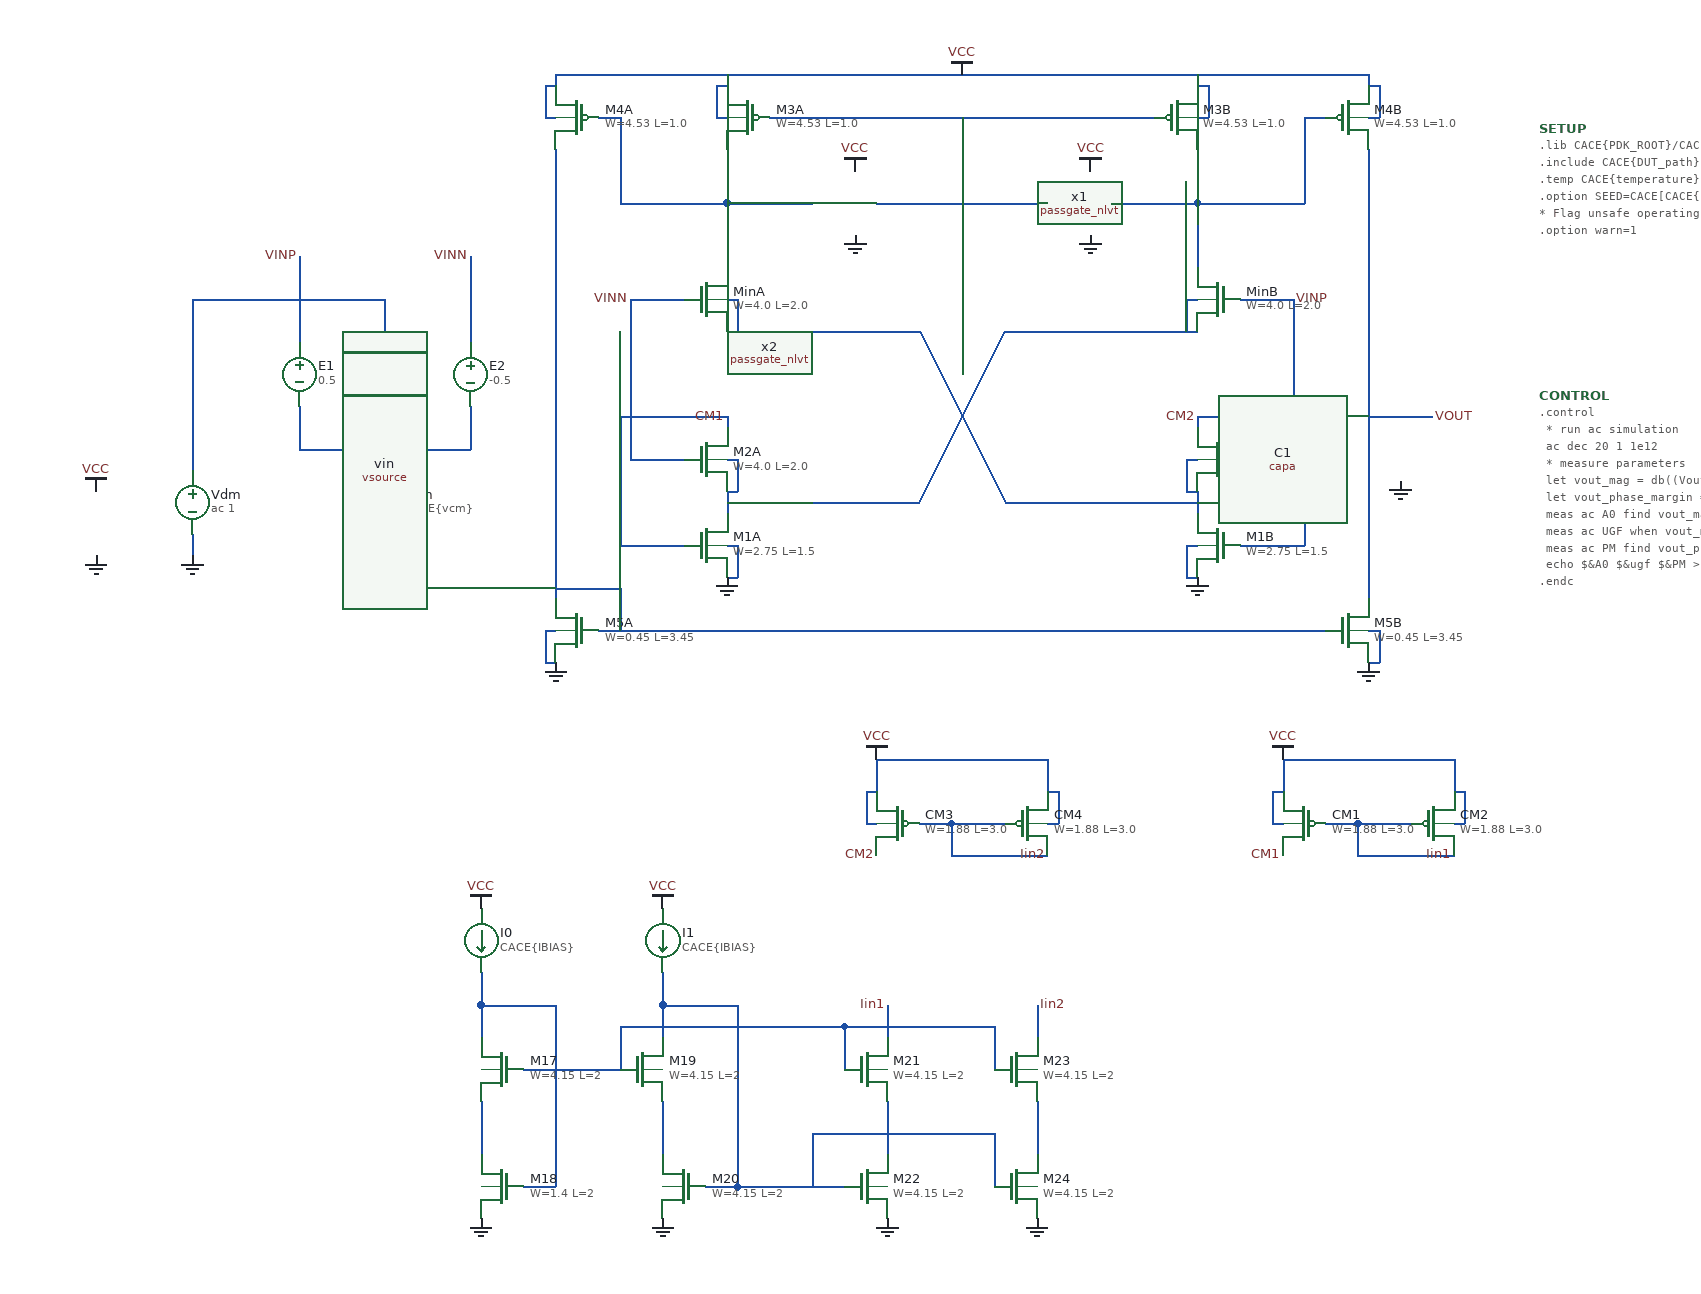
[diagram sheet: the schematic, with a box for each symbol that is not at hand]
v {xschem version=3.4.5 file_version=1.2
}
G {}
K {}
V {}
S {}
E {}
N 220 0 220 10 {
lab=CM2}
N -220 70 -220 90 {
lab=#net1}
N -320 0 -220 0 {
lab=CM1}
N -320 0 -320 120 {
lab=CM1}
N -320 120 -260 120 {
lab=CM1}
N 220 70 220 90 {
lab=#net2}
N -310 40 -260 40 {
lab=VINN}
N -310 -110 -260 -110 {
lab=VINN}
N 260 120 320 120 {
lab=CM2}
N 220 0 320 0 {
lab=CM2}
N 320 0 320 120 {
lab=CM2}
N 260 40 310 40 {
lab=VINP}
N 260 -110 310 -110 {
lab=VINP}
N -220 80 -40 80 {
lab=#net1}
N 40 -80 220 -80 {
lab=#net1}
N -220 -80 -40 -80 {
lab=#net2}
N 40 80 220 80 {
lab=#net2}
N 140 -200 220 -200 {
lab=#net3}
N -220 -200 -140 -200 {
lab=#net4}
N -80 -200 80 -200 {
lab=#net5}
N -180 -280 180 -280 {
lab=#net5}
N -380 -320 380 -320 {
lab=VCC}
N 320 -280 340 -280 {
lab=#net3}
N -340 -280 -320 -280 {
lab=#net4}
N -340 200 340 200 {
lab=#net6}
N -380 -250 -380 170 {
lab=#net6}
N -380 160 -320 160 {
lab=#net6}
N -320 160 -320 200 {
lab=#net6}
N 380 -250 380 170 {
lab=VOUT}
N -380 -320 -380 -310 {
lab=VCC}
N -220 -320 -220 -310 {
lab=VCC}
N 220 -320 220 -310 {
lab=VCC}
N 380 -320 380 -310 {
lab=VCC}
N 380 -0 440 0 {
lab=VOUT}
N -220 -110 -210 -110 {
lab=#net2}
N -210 -110 -210 -80 {
lab=#net2}
N 210 -110 220 -110 {
lab=#net1}
N 210 -110 210 -80 {
lab=#net1}
N -390 200 -380 200 {
lab=GND}
N -390 200 -390 230 {
lab=GND}
N -390 230 -380 230 {
lab=GND}
N -220 120 -210 120 {
lab=GND}
N -210 120 -210 150 {
lab=GND}
N -220 150 -210 150 {
lab=GND}
N -220 40 -210 40 {
lab=#net1}
N -210 40 -210 70 {
lab=#net1}
N -220 70 -210 70 {
lab=#net1}
N 460 380 470 380 {
lab=VCC}
N 470 350 470 380 {
lab=VCC}
N 460 350 470 350 {
lab=VCC}
N 210 120 220 120 {
lab=GND}
N 210 120 210 150 {
lab=GND}
N 210 150 220 150 {
lab=GND}
N 210 40 220 40 {
lab=#net2}
N 210 40 210 70 {
lab=#net2}
N 210 70 220 70 {
lab=#net2}
N 380 200 390 200 {
lab=GND}
N 390 200 390 230 {
lab=GND}
N 380 230 390 230 {
lab=GND}
N 220 -280 230 -280 {
lab=VCC}
N 230 -310 230 -280 {
lab=VCC}
N 220 -310 230 -310 {
lab=VCC}
N 380 -280 390 -280 {
lab=VCC}
N 390 -310 390 -280 {
lab=VCC}
N 380 -310 390 -310 {
lab=VCC}
N -230 -280 -220 -280 {
lab=VCC}
N -230 -310 -230 -280 {
lab=VCC}
N -230 -310 -220 -310 {
lab=VCC}
N -390 -280 -380 -280 {
lab=VCC}
N -390 -310 -390 -280 {
lab=VCC}
N -390 -310 -380 -310 {
lab=VCC}
N -220 0 -220 10 {
lab=CM1}
N 340 380 370 380 {
lab=Iin1}
N 370 380 420 380 {
lab=Iin1}
N 370 380 370 410 {
lab=Iin1}
N 370 410 460 410 {
lab=Iin1}
N 300 320 370 320 {
lab=VCC}
N 370 320 460 320 {
lab=VCC}
N 460 320 460 350 {
lab=VCC}
N 300 320 300 350 {
lab=VCC}
N 290 380 300 380 {
lab=VCC}
N 290 350 300 350 {
lab=VCC}
N 290 350 290 380 {
lab=VCC}
N -320 -280 -320 -200 {
lab=#net4}
N -320 -200 -220 -200 {
lab=#net4}
N 320 -280 320 -200 {
lab=#net3}
N 220 -200 320 -200 {
lab=#net3}
N -40 80 40 -80 {
lab=#net1}
N 220 -250 220 -200 {
lab=#net3}
N 220 -200 220 -140 {
lab=#net3}
N 310 -110 310 40 {
lab=VINP}
N -40 -80 40 80 {
lab=#net2}
N -310 -110 -310 40 {
lab=VINN}
N -220 -250 -220 -200 {
lab=#net4}
N -220 -200 -220 -140 {
lab=#net4}
N 80 380 90 380 {
lab=VCC}
N 90 350 90 380 {
lab=VCC}
N 80 350 90 350 {
lab=VCC}
N -40 380 -10 380 {
lab=Iin2}
N -10 380 40 380 {
lab=Iin2}
N -10 380 -10 410 {
lab=Iin2}
N -10 410 80 410 {
lab=Iin2}
N -80 320 -10 320 {
lab=VCC}
N -10 320 80 320 {
lab=VCC}
N 80 320 80 350 {
lab=VCC}
N -80 320 -80 350 {
lab=VCC}
N -90 380 -80 380 {
lab=VCC}
N -90 350 -80 350 {
lab=VCC}
N -90 350 -90 380 {
lab=VCC}
N -0 -280 -0 -200 {
lab=#net5}
N -540 -60 -500 -60 {
lab=#net7}
N -720 -110 -720 50 {
lab=#net7}
N -720 -110 -540 -110 {
lab=#net7}
N -720 110 -720 130 {
lab=GND}
N -540 110 -540 130 {
lab=GND}
N -540 30 -460 30 {
lab=#net8}
N -540 30 -540 50 {
lab=#net8}
N -540 -20 -500 -20 {
lab=GND}
N -540 -20 -540 0 {
lab=GND}
N -620 -10 -620 30 {
lab=#net8}
N -460 -10 -460 30 {
lab=#net8}
N -540 -110 -540 -60 {
lab=#net7}
N -460 -150 -460 -70 {
lab=VINN}
N -620 -150 -620 -70 {
lab=VINP}
N -620 30 -540 30 {
lab=#net8}
N -580 -20 -540 -20 {
lab=GND}
N -580 -60 -540 -60 {
lab=#net7}
N -450 550 -450 580 {
lab=#net9}
N -450 640 -450 690 {
lab=#net10}
N -410 720 -380 720 {
lab=#net9}
N -380 550 -380 720 {
lab=#net9}
N -450 550 -380 550 {
lab=#net9}
N -280 550 -280 580 {
lab=GND}
N -280 640 -280 690 {
lab=#net11}
N -240 720 -210 720 {
lab=GND}
N -210 550 -210 720 {
lab=GND}
N -280 550 -210 550 {
lab=GND}
N -70 550 -70 580 {
lab=Iin1}
N -70 640 -70 690 {
lab=#net12}
N -410 610 -380 610 {
lab=#net9}
N -210 720 -110 720 {
lab=GND}
N -450 520 -450 550 {
lab=#net9}
N -280 520 -280 550 {
lab=GND}
N -380 610 -320 610 {
lab=#net9}
N -320 570 -320 610 {
lab=#net9}
N -320 570 -110 570 {
lab=#net9}
N -110 570 -110 610 {
lab=#net9}
N 70 550 70 580 {
lab=Iin2}
N 70 640 70 690 {
lab=#net13}
N 30 570 30 610 {
lab=#net9}
N -140 670 -140 720 {
lab=GND}
N -140 670 30 670 {
lab=GND}
N 30 670 30 720 {
lab=GND}
N -110 570 30 570 {
lab=#net9}
C {sky130_fd_pr/nfet_01v8.sym} 240 120 0 1 {name=M1B
W=2.75
L=1.5
nf=1
mult=1
ad="'int((nf+1)/2) * W/nf * 0.29'" 
pd="'2*int((nf+1)/2) * (W/nf + 0.29)'"
as="'int((nf+2)/2) * W/nf * 0.29'" 
ps="'2*int((nf+2)/2) * (W/nf + 0.29)'"
nrd="'0.29 / W'" nrs="'0.29 / W'"
sa=0 sb=0 sd=0
model=nfet_01v8
spiceprefix=X
}
C {sky130_fd_pr/nfet_01v8.sym} 240 40 0 1 {name=M2B
W=4.0
L=2.0
nf=1
mult=1
ad="'int((nf+1)/2) * W/nf * 0.29'" 
pd="'2*int((nf+1)/2) * (W/nf + 0.29)'"
as="'int((nf+2)/2) * W/nf * 0.29'" 
ps="'2*int((nf+2)/2) * (W/nf + 0.29)'"
nrd="'0.29 / W'" nrs="'0.29 / W'"
sa=0 sb=0 sd=0
model=nfet_01v8
spiceprefix=X
}
C {devices/gnd.sym} 220 150 0 0 {name=l1 lab=GND}
C {devices/lab_pin.sym} -310 -110 0 0 {name=p1 sig_type=std_logic lab=VINN}
C {sky130_fd_pr/nfet_01v8.sym} -240 120 0 0 {name=M1A
W=2.75
L=1.5
nf=1
mult=1
ad="'int((nf+1)/2) * W/nf * 0.29'" 
pd="'2*int((nf+1)/2) * (W/nf + 0.29)'"
as="'int((nf+2)/2) * W/nf * 0.29'" 
ps="'2*int((nf+2)/2) * (W/nf + 0.29)'"
nrd="'0.29 / W'" nrs="'0.29 / W'"
sa=0 sb=0 sd=0
model=nfet_01v8
spiceprefix=X
}
C {sky130_fd_pr/nfet_01v8.sym} -240 40 0 0 {name=M2A
W=4.0
L=2.0
nf=1
mult=1
ad="'int((nf+1)/2) * W/nf * 0.29'" 
pd="'2*int((nf+1)/2) * (W/nf + 0.29)'"
as="'int((nf+2)/2) * W/nf * 0.29'" 
ps="'2*int((nf+2)/2) * (W/nf + 0.29)'"
nrd="'0.29 / W'" nrs="'0.29 / W'"
sa=0 sb=0 sd=0
model=nfet_01v8
spiceprefix=X
}
C {devices/gnd.sym} -220 150 0 1 {name=l2 lab=GND}
C {devices/vdd.sym} 300 320 0 0 {name=l3 lab=VCC}
C {sky130_fd_pr/pfet_01v8_lvt.sym} 320 380 0 1 {name=CM1
W=1.88
L=3.0
nf=1
mult=2
ad="'int((nf+1)/2) * W/nf * 0.29'" 
pd="'2*int((nf+1)/2) * (W/nf + 0.29)'"
as="'int((nf+2)/2) * W/nf * 0.29'" 
ps="'2*int((nf+2)/2) * (W/nf + 0.29)'"
nrd="'0.29 / W'" nrs="'0.29 / W'"
sa=0 sb=0 sd=0
model=pfet_01v8_lvt
spiceprefix=X
}
C {sky130_fd_pr/pfet_01v8_lvt.sym} 440 380 0 0 {name=CM2
W=1.88
L=3.0
nf=1
mult=2
ad="'int((nf+1)/2) * W/nf * 0.29'" 
pd="'2*int((nf+1)/2) * (W/nf + 0.29)'"
as="'int((nf+2)/2) * W/nf * 0.29'" 
ps="'2*int((nf+2)/2) * (W/nf + 0.29)'"
nrd="'0.29 / W'" nrs="'0.29 / W'"
sa=0 sb=0 sd=0
model=pfet_01v8_lvt
spiceprefix=X
}
C {devices/lab_pin.sym} 310 -110 0 1 {name=p6 sig_type=std_logic lab=VINP
}
C {sky130_fd_pr/pfet_01v8_lvt.sym} 200 -280 0 0 {name=M3B
W=4.53
L=1.0
nf=1
mult=2
ad="'int((nf+1)/2) * W/nf * 0.29'" 
pd="'2*int((nf+1)/2) * (W/nf + 0.29)'"
as="'int((nf+2)/2) * W/nf * 0.29'" 
ps="'2*int((nf+2)/2) * (W/nf + 0.29)'"
nrd="'0.29 / W'" nrs="'0.29 / W'"
sa=0 sb=0 sd=0
model=pfet_01v8_lvt
spiceprefix=X
}
C {sky130_fd_pr/pfet_01v8_lvt.sym} -200 -280 0 1 {name=M3A
W=4.53
L=1.0
nf=1
mult=2
ad="'int((nf+1)/2) * W/nf * 0.29'" 
pd="'2*int((nf+1)/2) * (W/nf + 0.29)'"
as="'int((nf+2)/2) * W/nf * 0.29'" 
ps="'2*int((nf+2)/2) * (W/nf + 0.29)'"
nrd="'0.29 / W'" nrs="'0.29 / W'"
sa=0 sb=0 sd=0
model=pfet_01v8_lvt
spiceprefix=X
}
C {devices/vdd.sym} 0 -320 0 0 {name=l6 lab=VCC}
C {sky130_fd_pr/pfet_01v8_lvt.sym} 360 -280 0 0 {name=M4B
W=4.53
L=1.0
nf=1
mult=2
ad="'int((nf+1)/2) * W/nf * 0.29'" 
pd="'2*int((nf+1)/2) * (W/nf + 0.29)'"
as="'int((nf+2)/2) * W/nf * 0.29'" 
ps="'2*int((nf+2)/2) * (W/nf + 0.29)'"
nrd="'0.29 / W'" nrs="'0.29 / W'"
sa=0 sb=0 sd=0
model=pfet_01v8_lvt
spiceprefix=X
}
C {sky130_fd_pr/pfet_01v8_lvt.sym} -360 -280 0 1 {name=M4A
W=4.53
L=1.0
nf=1
mult=2
ad="'int((nf+1)/2) * W/nf * 0.29'" 
pd="'2*int((nf+1)/2) * (W/nf + 0.29)'"
as="'int((nf+2)/2) * W/nf * 0.29'" 
ps="'2*int((nf+2)/2) * (W/nf + 0.29)'"
nrd="'0.29 / W'" nrs="'0.29 / W'"
sa=0 sb=0 sd=0
model=pfet_01v8_lvt
spiceprefix=X
}
C {devices/gnd.sym} -380 230 0 1 {name=l8 lab=GND}
C {devices/gnd.sym} 380 230 0 1 {name=l9 lab=GND}
C {devices/lab_pin.sym} 440 0 2 0 {name=p2 sig_type=std_logic lab=VOUT}
C {devices/lab_pin.sym} -620 -150 2 1 {name=p4 sig_type=std_logic lab=VINP
}
C {devices/lab_pin.sym} -460 -150 0 0 {name=p5 sig_type=std_logic lab=VINN}
C {devices/capa.sym} 410 30 0 0 {name=C1
m=1
value=CACE\{cl\}
footprint=1206
device="ceramic capacitor"}
C {devices/gnd.sym} 410 60 0 0 {name=l12 lab=GND}
C {sky130_fd_pr/nfet_01v8.sym} -360 200 0 1 {name=M5A
W=0.45
L=3.45
nf=1
mult=2
ad="'int((nf+1)/2) * W/nf * 0.29'" 
pd="'2*int((nf+1)/2) * (W/nf + 0.29)'"
as="'int((nf+2)/2) * W/nf * 0.29'" 
ps="'2*int((nf+2)/2) * (W/nf + 0.29)'"
nrd="'0.29 / W'" nrs="'0.29 / W'"
sa=0 sb=0 sd=0
model=nfet_01v8
spiceprefix=X
}
C {sky130_fd_pr/nfet_01v8.sym} 360 200 0 0 {name=M5B
W=0.45
L=3.45
nf=1
mult=2
ad="'int((nf+1)/2) * W/nf * 0.29'" 
pd="'2*int((nf+1)/2) * (W/nf + 0.29)'"
as="'int((nf+2)/2) * W/nf * 0.29'" 
ps="'2*int((nf+2)/2) * (W/nf + 0.29)'"
nrd="'0.29 / W'" nrs="'0.29 / W'"
sa=0 sb=0 sd=0
model=nfet_01v8
spiceprefix=X
}
C {sky130_fd_pr/nfet_01v8.sym} -240 -110 0 0 {name=MinA
W=4.0
L=2.0
nf=1
mult=1
ad="'int((nf+1)/2) * W/nf * 0.29'" 
pd="'2*int((nf+1)/2) * (W/nf + 0.29)'"
as="'int((nf+2)/2) * W/nf * 0.29'" 
ps="'2*int((nf+2)/2) * (W/nf + 0.29)'"
nrd="'0.29 / W'" nrs="'0.29 / W'"
sa=0 sb=0 sd=0
model=nfet_01v8
spiceprefix=X
}
C {sky130_fd_pr/nfet_01v8.sym} 240 -110 0 1 {name=MinB
W=4.0
L=2.0
nf=1
mult=1
ad="'int((nf+1)/2) * W/nf * 0.29'" 
pd="'2*int((nf+1)/2) * (W/nf + 0.29)'"
as="'int((nf+2)/2) * W/nf * 0.29'" 
ps="'2*int((nf+2)/2) * (W/nf + 0.29)'"
nrd="'0.29 / W'" nrs="'0.29 / W'"
sa=0 sb=0 sd=0
model=nfet_01v8
spiceprefix=X
}
C {devices/code_shown.sym} 540 -270 0 0 {name=SETUP
simulator=ngspice
only_toplevel=false
value="
.lib CACE\{PDK_ROOT\}/CACE\{PDK\}/libs.tech/combined/sky130.lib.spice CACE\{corner\}

.include CACE\{DUT_path\}

.temp CACE\{temperature\}

.option SEED=CACE[CACE\{seed=12345\} + CACE\{iterations=0\}]

* Flag unsafe operating conditions (exceeds models' specified limits)
.option warn=1
"}
C {devices/code_shown.sym} 540 -20 0 0 {name=CONTROL
simulator=ngspice
only_toplevel=false
value="
.control

    * run ac simulation
    ac dec 20 1 1e12

    * measure parameters
    let vout_mag = db((Vout))
    let vout_phase_margin =  phase(v(Vout)) * 180/pi + 180
    meas ac A0 find vout_mag at=1
    meas ac UGF when vout_mag=0
    meas ac PM find vout_phase_margin when vout_mag=0

    echo $&A0 $&ugf $&PM > CACE\{simpath\}/CACE\{filename\}_CACE\{N\}.data
.endc
"}
C {sky130_tests/passgate_nlvt.sym} -100 -200 2 1 {name=x2 W_N=0.5 L_N=4 W_P=3 L_P=4 VCCBPIN=VCC VSSBPIN=VSS m=1}
C {sky130_tests/passgate_nlvt.sym} 120 -200 2 0 {name=x1 W_N=0.5 L_N=4 W_P=3 L_P=4 VCCBPIN=VCC VSSBPIN=VSS m=1}
C {devices/vdd.sym} -100 -230 0 0 {name=l20 lab=VCC}
C {devices/vdd.sym} 120 -230 0 0 {name=l21 lab=VCC}
C {devices/gnd.sym} -100 -170 0 1 {name=l22 lab=GND}
C {devices/gnd.sym} 120 -170 0 0 {name=l23 lab=GND}
C {devices/lab_pin.sym} -220 0 1 0 {name=p8 sig_type=std_logic lab=CM1}
C {devices/lab_pin.sym} 300 410 3 0 {name=p9 sig_type=std_logic lab=CM1}
C {devices/lab_pin.sym} 220 0 1 0 {name=p7 sig_type=std_logic lab=CM2}
C {devices/vdd.sym} -80 320 0 0 {name=l7 lab=VCC}
C {sky130_fd_pr/pfet_01v8_lvt.sym} -60 380 0 1 {name=CM3
W=1.88
L=3.0
nf=1
mult=2
ad="'int((nf+1)/2) * W/nf * 0.29'" 
pd="'2*int((nf+1)/2) * (W/nf + 0.29)'"
as="'int((nf+2)/2) * W/nf * 0.29'" 
ps="'2*int((nf+2)/2) * (W/nf + 0.29)'"
nrd="'0.29 / W'" nrs="'0.29 / W'"
sa=0 sb=0 sd=0
model=pfet_01v8_lvt
spiceprefix=X
}
C {sky130_fd_pr/pfet_01v8_lvt.sym} 60 380 0 0 {name=CM4
W=1.88
L=3.0
nf=1
mult=2
ad="'int((nf+1)/2) * W/nf * 0.29'" 
pd="'2*int((nf+1)/2) * (W/nf + 0.29)'"
as="'int((nf+2)/2) * W/nf * 0.29'" 
ps="'2*int((nf+2)/2) * (W/nf + 0.29)'"
nrd="'0.29 / W'" nrs="'0.29 / W'"
sa=0 sb=0 sd=0
model=pfet_01v8_lvt
spiceprefix=X
}
C {devices/lab_pin.sym} -80 410 3 0 {name=p11 sig_type=std_logic lab=CM2}
C {devices/vcvs.sym} -620 -40 0 1 {name=E1 value=0.5}
C {devices/vcvs.sym} -460 -40 0 0 {name=E2 value=-0.5}
C {devices/vsource.sym} -720 80 0 0 {name=Vdm value="ac 1" savecurrent=false}
C {devices/vsource.sym} -540 80 0 0 {name=Vcm value=CACE\{vcm\} savecurrent=false}
C {devices/gnd.sym} -720 130 0 0 {name=l10 lab=GND}
C {devices/gnd.sym} -540 130 0 0 {name=l11 lab=GND}
C {devices/gnd.sym} -540 0 0 0 {name=l13 lab=GND}
C {devices/vsource.sym} -810 100 0 0 {name=vin value=CACE\{vcc\} savecurrent=false}
C {devices/gnd.sym} -810 130 0 0 {name=l14 lab=GND}
C {devices/vdd.sym} -810 70 0 0 {name=l15 lab=VCC}
C {devices/isource.sym} -450 490 0 0 {name=I0 value=CACE\{IBIAS\}}
C {devices/isource.sym} -280 490 0 0 {name=I1 value=CACE\{IBIAS\}}
C {sky130_fd_pr/nfet3_01v8.sym} -430 610 0 1 {name=M17
L=2
W=4.15
body=GND
nf=2
mult=1
ad="'int((nf+1)/2) * W/nf * 0.29'" 
pd="'2*int((nf+1)/2) * (W/nf + 0.29)'"
as="'int((nf+2)/2) * W/nf * 0.29'" 
ps="'2*int((nf+2)/2) * (W/nf + 0.29)'"
nrd="'0.29 / W'" nrs="'0.29 / W'"
sa=0 sb=0 sd=0
model=nfet_01v8
spiceprefix=X
}
C {sky130_fd_pr/nfet3_01v8.sym} -430 720 0 1 {name=M18
L=2
W=1.4
body=GND
nf=1
mult=1
ad="'int((nf+1)/2) * W/nf * 0.29'" 
pd="'2*int((nf+1)/2) * (W/nf + 0.29)'"
as="'int((nf+2)/2) * W/nf * 0.29'" 
ps="'2*int((nf+2)/2) * (W/nf + 0.29)'"
nrd="'0.29 / W'" nrs="'0.29 / W'"
sa=0 sb=0 sd=0
model=nfet_01v8
spiceprefix=X
}
C {sky130_fd_pr/nfet3_01v8.sym} -300 610 0 0 {name=M19
L=2
W=4.15
body=GND
nf=2
mult=1
ad="'int((nf+1)/2) * W/nf * 0.29'" 
pd="'2*int((nf+1)/2) * (W/nf + 0.29)'"
as="'int((nf+2)/2) * W/nf * 0.29'" 
ps="'2*int((nf+2)/2) * (W/nf + 0.29)'"
nrd="'0.29 / W'" nrs="'0.29 / W'"
sa=0 sb=0 sd=0
model=nfet_01v8
spiceprefix=X
}
C {sky130_fd_pr/nfet3_01v8.sym} -260 720 0 1 {name=M20
L=2
W=4.15
body=GND
nf=2
mult=1
ad="'int((nf+1)/2) * W/nf * 0.29'" 
pd="'2*int((nf+1)/2) * (W/nf + 0.29)'"
as="'int((nf+2)/2) * W/nf * 0.29'" 
ps="'2*int((nf+2)/2) * (W/nf + 0.29)'"
nrd="'0.29 / W'" nrs="'0.29 / W'"
sa=0 sb=0 sd=0
model=nfet_01v8
spiceprefix=X
}
C {sky130_fd_pr/nfet3_01v8.sym} -90 610 0 0 {name=M21
L=2
W=4.15
body=GND
nf=2
mult=1
ad="'int((nf+1)/2) * W/nf * 0.29'" 
pd="'2*int((nf+1)/2) * (W/nf + 0.29)'"
as="'int((nf+2)/2) * W/nf * 0.29'" 
ps="'2*int((nf+2)/2) * (W/nf + 0.29)'"
nrd="'0.29 / W'" nrs="'0.29 / W'"
sa=0 sb=0 sd=0
model=nfet_01v8
spiceprefix=X
}
C {sky130_fd_pr/nfet3_01v8.sym} -90 720 0 0 {name=M22
L=2
W=4.15
body=GND
nf=2
mult=1
ad="'int((nf+1)/2) * W/nf * 0.29'" 
pd="'2*int((nf+1)/2) * (W/nf + 0.29)'"
as="'int((nf+2)/2) * W/nf * 0.29'" 
ps="'2*int((nf+2)/2) * (W/nf + 0.29)'"
nrd="'0.29 / W'" nrs="'0.29 / W'"
sa=0 sb=0 sd=0
model=nfet_01v8
spiceprefix=X
}
C {devices/gnd.sym} -70 750 0 0 {name=l16 lab=GND}
C {devices/gnd.sym} -280 750 0 0 {name=l17 lab=GND}
C {devices/gnd.sym} -450 750 0 0 {name=l18 lab=GND}
C {devices/lab_pin.sym} -70 550 0 0 {name=p41 sig_type=std_logic lab=Iin1}
C {devices/lab_pin.sym} 70 550 0 1 {name=p42 sig_type=std_logic lab=Iin2}
C {sky130_fd_pr/nfet3_01v8.sym} 50 610 0 0 {name=M23
L=2
W=4.15
body=GND
nf=2
mult=1
ad="'int((nf+1)/2) * W/nf * 0.29'" 
pd="'2*int((nf+1)/2) * (W/nf + 0.29)'"
as="'int((nf+2)/2) * W/nf * 0.29'" 
ps="'2*int((nf+2)/2) * (W/nf + 0.29)'"
nrd="'0.29 / W'" nrs="'0.29 / W'"
sa=0 sb=0 sd=0
model=nfet_01v8
spiceprefix=X
}
C {sky130_fd_pr/nfet3_01v8.sym} 50 720 0 0 {name=M24
L=2
W=4.15
body=GND
nf=2
mult=1
ad="'int((nf+1)/2) * W/nf * 0.29'" 
pd="'2*int((nf+1)/2) * (W/nf + 0.29)'"
as="'int((nf+2)/2) * W/nf * 0.29'" 
ps="'2*int((nf+2)/2) * (W/nf + 0.29)'"
nrd="'0.29 / W'" nrs="'0.29 / W'"
sa=0 sb=0 sd=0
model=nfet_01v8
spiceprefix=X
}
C {devices/gnd.sym} 70 750 0 0 {name=l19 lab=GND}
C {devices/lab_pin.sym} 460 410 3 0 {name=p3 sig_type=std_logic lab=Iin1}
C {devices/lab_pin.sym} 80 410 1 1 {name=p10 sig_type=std_logic lab=Iin2}
C {devices/vdd.sym} -450 460 0 0 {name=l4 lab=VCC}
C {devices/vdd.sym} -280 460 0 0 {name=l5 lab=VCC}
